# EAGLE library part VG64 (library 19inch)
PCB EUROCARD, 64-pin type C/AC, 2.54 mm

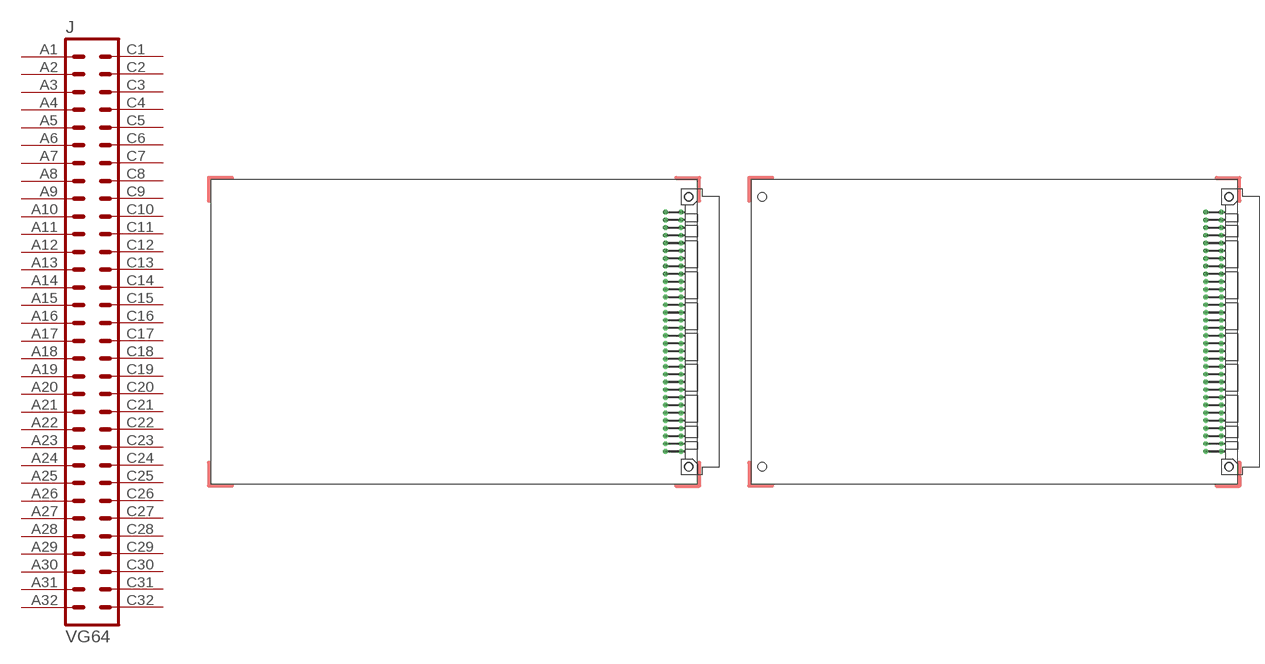
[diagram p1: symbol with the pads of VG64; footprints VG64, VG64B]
Designator prefix J

## VG64  [VG64]
A1  A1  pas
A2  A2  pas
A3  A3  pas
A4  A4  pas
A5  A5  pas
A6  A6  pas
A7  A7  pas
A8  A8  pas
A9  A9  pas
A10  A10  pas
A11  A11  pas
A12  A12  pas
A13  A13  pas
A14  A14  pas
A15  A15  pas
A16  A16  pas
A17  A17  pas
A18  A18  pas
A19  A19  pas
A20  A20  pas
A21  A21  pas
A22  A22  pas
A23  A23  pas
A24  A24  pas
A25  A25  pas
A26  A26  pas
A27  A27  pas
A28  A28  pas
A29  A29  pas
A30  A30  pas
A31  A31  pas
A32  A32  pas
C1  C1  pas
C2  C2  pas
C3  C3  pas
C4  C4  pas
C5  C5  pas
C6  C6  pas
C7  C7  pas
C8  C8  pas
C9  C9  pas
C10  C10  pas
C11  C11  pas
C12  C12  pas
C13  C13  pas
C14  C14  pas
C15  C15  pas
C16  C16  pas
C17  C17  pas
C18  C18  pas
C19  C19  pas
C20  C20  pas
C21  C21  pas
C22  C22  pas
C23  C23  pas
C24  C24  pas
C25  C25  pas
C26  C26  pas
C27  C27  pas
C28  C28  pas
C29  C29  pas
C30  C30  pas
C31  C31  pas
C32  C32  pas

## VG64B  [VG64B]
Pads as for VG64

## VG64K  [VG64K]
Pads as for VG64

## VG64KB  [VG64KB]
Pads as for VG64

## VG64P  [VG64P]
Pads as for VG64

## Footprint VG64 (pad centres in mm)
EUROCARD, 2 holes, C/AC, 2.54
drill 0.914 pad 1.6 round: A1 154.94,39.37
drill 0.914 pad 1.6 octagon: A2 154.94,36.83; A3 154.94,34.29; A4 154.94,31.75; A5 154.94,29.21; A6 154.94,26.67; A7 154.94,24.13; A8 154.94,21.59; A9 154.94,19.05; A10 154.94,16.51; A11 154.94,13.97; A12 154.94,11.43; A13 154.94,8.89; A14 154.94,6.35; A15 154.94,3.81; A16 154.94,1.27; A17 154.94,-1.27; A18 154.94,-3.81; A19 154.94,-6.35; A20 154.94,-8.89; A21 154.94,-11.43; A22 154.94,-13.97; A23 154.94,-16.51; A24 154.94,-19.05; A25 154.94,-21.59; A26 154.94,-24.13; A27 154.94,-26.67; A28 154.94,-29.21; A29 154.94,-31.75; A30 154.94,-34.29; A31 154.94,-36.83; A32 154.94,-39.37; C1 149.86,39.37; C2 149.86,36.83; C3 149.86,34.29; C4 149.86,31.75; C5 149.86,29.21; C6 149.86,26.67; C7 149.86,24.13; C8 149.86,21.59; C9 149.86,19.05; C10 149.86,16.51; C11 149.86,13.97; C12 149.86,11.43; C13 149.86,8.89; C14 149.86,6.35; C15 149.86,3.81; C16 149.86,1.27; C17 149.86,-1.27; C18 149.86,-3.81; C19 149.86,-6.35; C20 149.86,-8.89; C21 149.86,-11.43; C22 149.86,-13.97; C23 149.86,-16.51; C24 149.86,-19.05; C25 149.86,-21.59; C26 149.86,-24.13; C27 149.86,-26.67; C28 149.86,-29.21; C29 149.86,-31.75; C30 149.86,-34.29; C31 149.86,-36.83; C32 149.86,-39.37
hole 2.794 at 157.48,44.45
hole 2.794 at 157.48,-44.45

## Footprint VG64B (pad centres in mm)
EUROCARD, 4 holes, C/AC, 2.54
drill 0.914 pad 1.6 round: A1 154.94,39.37
drill 0.914 pad 1.6 octagon: A2 154.94,36.83; A3 154.94,34.29; A4 154.94,31.75; A5 154.94,29.21; A6 154.94,26.67; A7 154.94,24.13; A8 154.94,21.59; A9 154.94,19.05; A10 154.94,16.51; A11 154.94,13.97; A12 154.94,11.43; A13 154.94,8.89; A14 154.94,6.35; A15 154.94,3.81; A16 154.94,1.27; A17 154.94,-1.27; A18 154.94,-3.81; A19 154.94,-6.35; A20 154.94,-8.89; A21 154.94,-11.43; A22 154.94,-13.97; A23 154.94,-16.51; A24 154.94,-19.05; A25 154.94,-21.59; A26 154.94,-24.13; A27 154.94,-26.67; A28 154.94,-29.21; A29 154.94,-31.75; A30 154.94,-34.29; A31 154.94,-36.83; A32 154.94,-39.37; C1 149.86,39.37; C2 149.86,36.83; C3 149.86,34.29; C4 149.86,31.75; C5 149.86,29.21; C6 149.86,26.67; C7 149.86,24.13; C8 149.86,21.59; C9 149.86,19.05; C10 149.86,16.51; C11 149.86,13.97; C12 149.86,11.43; C13 149.86,8.89; C14 149.86,6.35; C15 149.86,3.81; C16 149.86,1.27; C17 149.86,-1.27; C18 149.86,-3.81; C19 149.86,-6.35; C20 149.86,-8.89; C21 149.86,-11.43; C22 149.86,-13.97; C23 149.86,-16.51; C24 149.86,-19.05; C25 149.86,-21.59; C26 149.86,-24.13; C27 149.86,-26.67; C28 149.86,-29.21; C29 149.86,-31.75; C30 149.86,-34.29; C31 149.86,-36.83; C32 149.86,-39.37
hole 2.794 at 157.48,44.45
hole 2.794 at 157.48,-44.45
hole 2.794 at 3.81,-44.45
hole 2.794 at 3.81,44.45

## Footprint VG64K (pad centres in mm)
EUROCARD, 2 holes, C/ABC, 2.54
drill 0.914 pad 1.6 round: A1 154.94,39.37
drill 0.914 pad 1.6 octagon: A2 154.94,36.83; A3 154.94,34.29; A4 154.94,31.75; A5 154.94,29.21; A6 154.94,26.67; A7 154.94,24.13; A8 154.94,21.59; A9 154.94,19.05; A10 154.94,16.51; A11 154.94,13.97; A12 154.94,11.43; A13 154.94,8.89; A14 154.94,6.35; A15 154.94,3.81; A16 154.94,1.27; A17 154.94,-1.27; A18 154.94,-3.81; A19 154.94,-6.35; A20 154.94,-8.89; A21 154.94,-11.43; A22 154.94,-13.97; A23 154.94,-16.51; A24 154.94,-19.05; A25 154.94,-21.59; A26 154.94,-24.13; A27 154.94,-26.67; A28 154.94,-29.21; A29 154.94,-31.75; A30 154.94,-34.29; A31 154.94,-36.83; A32 154.94,-39.37; C1 149.86,39.37; C2 149.86,36.83; C3 149.86,34.29; C4 149.86,31.75; C5 149.86,29.21; C6 149.86,26.67; C7 149.86,24.13; C8 149.86,21.59; C9 149.86,19.05; C10 149.86,16.51; C11 149.86,13.97; C12 149.86,11.43; C13 149.86,8.89; C14 149.86,6.35; C15 149.86,3.81; C16 149.86,1.27; C17 149.86,-1.27; C18 149.86,-3.81; C19 149.86,-6.35; C20 149.86,-8.89; C21 149.86,-11.43; C22 149.86,-13.97; C23 149.86,-16.51; C24 149.86,-19.05; C25 149.86,-21.59; C26 149.86,-24.13; C27 149.86,-26.67; C28 149.86,-29.21; C29 149.86,-31.75; C30 149.86,-34.29; C31 149.86,-36.83; C32 149.86,-39.37
hole 2.794 at 157.48,44.45
hole 2.794 at 157.48,-44.45

## Footprint VG64KB (pad centres in mm)
EUROCARD, 4 holes, C/AC, 2.54
drill 0.914 pad 1.6 round: A1 154.94,39.37
drill 0.914 pad 1.6 octagon: A2 154.94,36.83; A3 154.94,34.29; A4 154.94,31.75; A5 154.94,29.21; A6 154.94,26.67; A7 154.94,24.13; A8 154.94,21.59; A9 154.94,19.05; A10 154.94,16.51; A11 154.94,13.97; A12 154.94,11.43; A13 154.94,8.89; A14 154.94,6.35; A15 154.94,3.81; A16 154.94,1.27; A17 154.94,-1.27; A18 154.94,-3.81; A19 154.94,-6.35; A20 154.94,-8.89; A21 154.94,-11.43; A22 154.94,-13.97; A23 154.94,-16.51; A24 154.94,-19.05; A25 154.94,-21.59; A26 154.94,-24.13; A27 154.94,-26.67; A28 154.94,-29.21; A29 154.94,-31.75; A30 154.94,-34.29; A31 154.94,-36.83; A32 154.94,-39.37; C1 149.86,39.37; C2 149.86,36.83; C3 149.86,34.29; C4 149.86,31.75; C5 149.86,29.21; C6 149.86,26.67; C7 149.86,24.13; C8 149.86,21.59; C9 149.86,19.05; C10 149.86,16.51; C11 149.86,13.97; C12 149.86,11.43; C13 149.86,8.89; C14 149.86,6.35; C15 149.86,3.81; C16 149.86,1.27; C17 149.86,-1.27; C18 149.86,-3.81; C19 149.86,-6.35; C20 149.86,-8.89; C21 149.86,-11.43; C22 149.86,-13.97; C23 149.86,-16.51; C24 149.86,-19.05; C25 149.86,-21.59; C26 149.86,-24.13; C27 149.86,-26.67; C28 149.86,-29.21; C29 149.86,-31.75; C30 149.86,-34.29; C31 149.86,-36.83; C32 149.86,-39.37
hole 2.794 at 157.48,44.45
hole 2.794 at 157.48,-44.45
hole 2.794 at 3.81,-44.45
hole 2.794 at 3.81,44.45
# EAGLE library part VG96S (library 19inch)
PCB EUROCARD, 96-pin type C/ABC, 2.54 mm

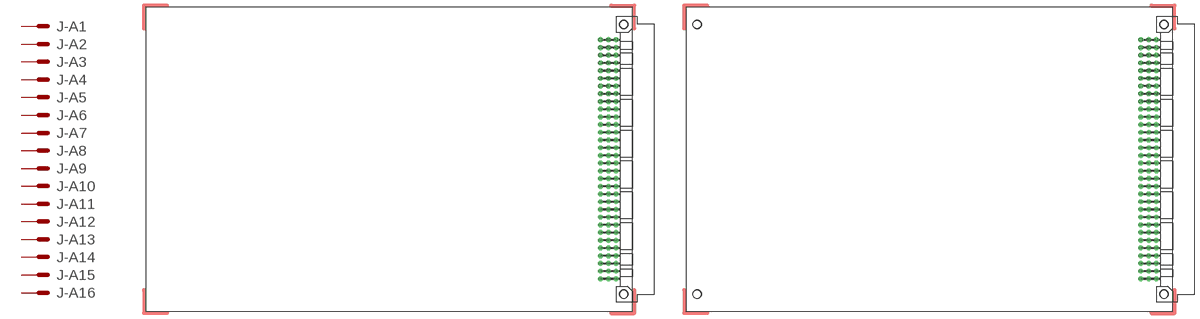
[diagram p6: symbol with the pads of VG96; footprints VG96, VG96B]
Designator prefix J; gates -A1=MS -A2=MS -A3=MS -A4=MS -A5=MS -A6=MS -A7=MS -A8=MS -A9=MS -A10=MS -A11=MS -A12=MS -A13=MS -A14=MS -A15=MS -A16=MS -A17=MS -A18=MS -A19=MS -A20=MS -A21=MS -A22=MS -A23=MS -A24=MS -A25=MS -A26=MS -A27=MS -A28=MS -A29=MS -A30=MS -A31=MS -A32=MS -B1=MS -B2=MS -B3=MS -B4=MS -B5=MS -B6=MS -B7=MS -B8=MS -B9=MS -B10=MS -B11=MS -B12=MS -B13=MS -B14=MS -B15=MS -B16=MS -B17=MS -B18=MS -B19=MS -B20=MS -B21=MS -B22=MS -B23=MS -B24=MS -B25=MS -B26=MS -B27=MS -B28=MS -B29=MS -B30=MS -B31=MS -B32=MS -C1=MS -C2=MS -C3=MS -C4=MS -C5=MS -C6=MS -C7=MS -C8=MS -C9=MS -C10=MS -C11=MS -C12=MS -C13=MS -C14=MS -C15=MS -C16=MS -C17=MS -C18=MS -C19=MS -C20=MS -C21=MS -C22=MS -C23=MS -C24=MS -C25=MS -C26=MS -C27=MS -C28=MS -C29=MS -C30=MS -C31=MS -C32=MSV

## VG96S  [VG96]
A1  -A1:MS  pas
A2  -A2:MS  pas
A3  -A3:MS  pas
A4  -A4:MS  pas
A5  -A5:MS  pas
A6  -A6:MS  pas
A7  -A7:MS  pas
A8  -A8:MS  pas
A9  -A9:MS  pas
A10  -A10:MS  pas
A11  -A11:MS  pas
A12  -A12:MS  pas
A13  -A13:MS  pas
A14  -A14:MS  pas
A15  -A15:MS  pas
A16  -A16:MS  pas
A17  -A17:MS  pas
A18  -A18:MS  pas
A19  -A19:MS  pas
A20  -A20:MS  pas
A21  -A21:MS  pas
A22  -A22:MS  pas
A23  -A23:MS  pas
A24  -A24:MS  pas
A25  -A25:MS  pas
A26  -A26:MS  pas
A27  -A27:MS  pas
A28  -A28:MS  pas
A29  -A29:MS  pas
A30  -A30:MS  pas
A31  -A31:MS  pas
A32  -A32:MS  pas
B1  -B1:MS  pas
B2  -B2:MS  pas
B3  -B3:MS  pas
B4  -B4:MS  pas
B5  -B5:MS  pas
B6  -B6:MS  pas
B7  -B7:MS  pas
B8  -B8:MS  pas
B9  -B9:MS  pas
B10  -B10:MS  pas
B11  -B11:MS  pas
B12  -B12:MS  pas
B13  -B13:MS  pas
B14  -B14:MS  pas
B15  -B15:MS  pas
B16  -B16:MS  pas
B17  -B17:MS  pas
B18  -B18:MS  pas
B19  -B19:MS  pas
B20  -B20:MS  pas
B21  -B21:MS  pas
B22  -B22:MS  pas
B23  -B23:MS  pas
B24  -B24:MS  pas
B25  -B25:MS  pas
B26  -B26:MS  pas
B27  -B27:MS  pas
B28  -B28:MS  pas
B29  -B29:MS  pas
B30  -B30:MS  pas
B31  -B31:MS  pas
B32  -B32:MS  pas
C1  -C1:MS  pas
C2  -C2:MS  pas
C3  -C3:MS  pas
C4  -C4:MS  pas
C5  -C5:MS  pas
C6  -C6:MS  pas
C7  -C7:MS  pas
C8  -C8:MS  pas
C9  -C9:MS  pas
C10  -C10:MS  pas
C11  -C11:MS  pas
C12  -C12:MS  pas
C13  -C13:MS  pas
C14  -C14:MS  pas
C15  -C15:MS  pas
C16  -C16:MS  pas
C17  -C17:MS  pas
C18  -C18:MS  pas
C19  -C19:MS  pas
C20  -C20:MS  pas
C21  -C21:MS  pas
C22  -C22:MS  pas
C23  -C23:MS  pas
C24  -C24:MS  pas
C25  -C25:MS  pas
C26  -C26:MS  pas
C27  -C27:MS  pas
C28  -C28:MS  pas
C29  -C29:MS  pas
C30  -C30:MS  pas
C31  -C31:MS  pas
C32  -C32:MSV  pas

## VG96SB  [VG96B]
Pads as for VG96

## VG96SK  [VG96K]
Pads as for VG96

## VG96SKB  [VG96KB]
Pads as for VG96

## VG96SP  [VG96P]
Pads as for VG96

## Footprint VG96 (pad centres in mm)
EUROCARD, C/ABC, 2.54
drill 0.914 pad 1.6 round: A1 154.94,39.37
drill 0.914 pad 1.6 octagon: A2 154.94,36.83; A3 154.94,34.29; A4 154.94,31.75; A5 154.94,29.21; A6 154.94,26.67; A7 154.94,24.13; A8 154.94,21.59; A9 154.94,19.05; A10 154.94,16.51; A11 154.94,13.97; A12 154.94,11.43; A13 154.94,8.89; A14 154.94,6.35; A15 154.94,3.81; A16 154.94,1.27; A17 154.94,-1.27; A18 154.94,-3.81; A19 154.94,-6.35; A20 154.94,-8.89; A21 154.94,-11.43; A22 154.94,-13.97; A23 154.94,-16.51; A24 154.94,-19.05; A25 154.94,-21.59; A26 154.94,-24.13; A27 154.94,-26.67; A28 154.94,-29.21; A29 154.94,-31.75; A30 154.94,-34.29; A31 154.94,-36.83; A32 154.94,-39.37; B1 152.4,39.37; B2 152.4,36.83; B3 152.4,34.29; B4 152.4,31.75; B5 152.4,29.21; B6 152.4,26.67; B7 152.4,24.13; B8 152.4,21.59; B9 152.4,19.05; B10 152.4,16.51; B11 152.4,13.97; B12 152.4,11.43; B13 152.4,8.89; B14 152.4,6.35; B15 152.4,3.81; B16 152.4,1.27; B17 152.4,-1.27; B18 152.4,-3.81; B19 152.4,-6.35; B20 152.4,-8.89; B21 152.4,-11.43; B22 152.4,-13.97; B23 152.4,-16.51; B24 152.4,-19.05; B25 152.4,-21.59; B26 152.4,-24.13; B27 152.4,-26.67; B28 152.4,-29.21; B29 152.4,-31.75; B30 152.4,-34.29; B31 152.4,-36.83; B32 152.4,-39.37; C1 149.86,39.37; C2 149.86,36.83; C3 149.86,34.29; C4 149.86,31.75; C5 149.86,29.21; C6 149.86,26.67; C7 149.86,24.13; C8 149.86,21.59; C9 149.86,19.05; C10 149.86,16.51; C11 149.86,13.97; C12 149.86,11.43; C13 149.86,8.89; C14 149.86,6.35; C15 149.86,3.81; C16 149.86,1.27; C17 149.86,-1.27; C18 149.86,-3.81; C19 149.86,-6.35; C20 149.86,-8.89; C21 149.86,-11.43; C22 149.86,-13.97; C23 149.86,-16.51; C24 149.86,-19.05; C25 149.86,-21.59; C26 149.86,-24.13; C27 149.86,-26.67; C28 149.86,-29.21; C29 149.86,-31.75; C30 149.86,-34.29; C31 149.86,-36.83; C32 149.86,-39.37
hole 2.794 at 157.48,44.45
hole 2.794 at 157.48,-44.45

## Footprint VG96B (pad centres in mm)
EUROCARD, 4 holes, C/ABC, 2.54
drill 0.914 pad 1.6 round: A1 154.94,39.37
drill 0.914 pad 1.6 octagon: A2 154.94,36.83; A3 154.94,34.29; A4 154.94,31.75; A5 154.94,29.21; A6 154.94,26.67; A7 154.94,24.13; A8 154.94,21.59; A9 154.94,19.05; A10 154.94,16.51; A11 154.94,13.97; A12 154.94,11.43; A13 154.94,8.89; A14 154.94,6.35; A15 154.94,3.81; A16 154.94,1.27; A17 154.94,-1.27; A18 154.94,-3.81; A19 154.94,-6.35; A20 154.94,-8.89; A21 154.94,-11.43; A22 154.94,-13.97; A23 154.94,-16.51; A24 154.94,-19.05; A25 154.94,-21.59; A26 154.94,-24.13; A27 154.94,-26.67; A28 154.94,-29.21; A29 154.94,-31.75; A30 154.94,-34.29; A31 154.94,-36.83; A32 154.94,-39.37; B1 152.4,39.37; B2 152.4,36.83; B3 152.4,34.29; B4 152.4,31.75; B5 152.4,29.21; B6 152.4,26.67; B7 152.4,24.13; B8 152.4,21.59; B9 152.4,19.05; B10 152.4,16.51; B11 152.4,13.97; B12 152.4,11.43; B13 152.4,8.89; B14 152.4,6.35; B15 152.4,3.81; B16 152.4,1.27; B17 152.4,-1.27; B18 152.4,-3.81; B19 152.4,-6.35; B20 152.4,-8.89; B21 152.4,-11.43; B22 152.4,-13.97; B23 152.4,-16.51; B24 152.4,-19.05; B25 152.4,-21.59; B26 152.4,-24.13; B27 152.4,-26.67; B28 152.4,-29.21; B29 152.4,-31.75; B30 152.4,-34.29; B31 152.4,-36.83; B32 152.4,-39.37; C1 149.86,39.37; C2 149.86,36.83; C3 149.86,34.29; C4 149.86,31.75; C5 149.86,29.21; C6 149.86,26.67; C7 149.86,24.13; C8 149.86,21.59; C9 149.86,19.05; C10 149.86,16.51; C11 149.86,13.97; C12 149.86,11.43; C13 149.86,8.89; C14 149.86,6.35; C15 149.86,3.81; C16 149.86,1.27; C17 149.86,-1.27; C18 149.86,-3.81; C19 149.86,-6.35; C20 149.86,-8.89; C21 149.86,-11.43; C22 149.86,-13.97; C23 149.86,-16.51; C24 149.86,-19.05; C25 149.86,-21.59; C26 149.86,-24.13; C27 149.86,-26.67; C28 149.86,-29.21; C29 149.86,-31.75; C30 149.86,-34.29; C31 149.86,-36.83; C32 149.86,-39.37
hole 2.794 at 157.48,44.45
hole 2.794 at 157.48,-44.45
hole 2.794 at 3.81,44.45
hole 2.794 at 3.81,-44.45

## Footprint VG96K (pad centres in mm)
EUROCARD, 2 holes, C/ABC, 2.54
drill 0.914 pad 1.6 round: A1 154.94,39.37
drill 0.914 pad 1.6 octagon: A2 154.94,36.83; A3 154.94,34.29; A4 154.94,31.75; A5 154.94,29.21; A6 154.94,26.67; A7 154.94,24.13; A8 154.94,21.59; A9 154.94,19.05; A10 154.94,16.51; A11 154.94,13.97; A12 154.94,11.43; A13 154.94,8.89; A14 154.94,6.35; A15 154.94,3.81; A16 154.94,1.27; A17 154.94,-1.27; A18 154.94,-3.81; A19 154.94,-6.35; A20 154.94,-8.89; A21 154.94,-11.43; A22 154.94,-13.97; A23 154.94,-16.51; A24 154.94,-19.05; A25 154.94,-21.59; A26 154.94,-24.13; A27 154.94,-26.67; A28 154.94,-29.21; A29 154.94,-31.75; A30 154.94,-34.29; A31 154.94,-36.83; A32 154.94,-39.37; B1 152.4,39.37; B2 152.4,36.83; B3 152.4,34.29; B4 152.4,31.75; B5 152.4,29.21; B6 152.4,26.67; B7 152.4,24.13; B8 152.4,21.59; B9 152.4,19.05; B10 152.4,16.51; B11 152.4,13.97; B12 152.4,11.43; B13 152.4,8.89; B14 152.4,6.35; B15 152.4,3.81; B16 152.4,1.27; B17 152.4,-1.27; B18 152.4,-3.81; B19 152.4,-6.35; B20 152.4,-8.89; B21 152.4,-11.43; B22 152.4,-13.97; B23 152.4,-16.51; B24 152.4,-19.05; B25 152.4,-21.59; B26 152.4,-24.13; B27 152.4,-26.67; B28 152.4,-29.21; B29 152.4,-31.75; B30 152.4,-34.29; B31 152.4,-36.83; B32 152.4,-39.37; C1 149.86,39.37; C2 149.86,36.83; C3 149.86,34.29; C4 149.86,31.75; C5 149.86,29.21; C6 149.86,26.67; C7 149.86,24.13; C8 149.86,21.59; C9 149.86,19.05; C10 149.86,16.51; C11 149.86,13.97; C12 149.86,11.43; C13 149.86,8.89; C14 149.86,6.35; C15 149.86,3.81; C16 149.86,1.27; C17 149.86,-1.27; C18 149.86,-3.81; C19 149.86,-6.35; C20 149.86,-8.89; C21 149.86,-11.43; C22 149.86,-13.97; C23 149.86,-16.51; C24 149.86,-19.05; C25 149.86,-21.59; C26 149.86,-24.13; C27 149.86,-26.67; C28 149.86,-29.21; C29 149.86,-31.75; C30 149.86,-34.29; C31 149.86,-36.83; C32 149.86,-39.37
hole 2.794 at 157.48,44.45
hole 2.794 at 157.48,-44.45

## Footprint VG96KB (pad centres in mm)
EUROCARD, 4 holes, C/ABC, 2.54
drill 0.914 pad 1.6 round: A1 154.94,39.37
drill 0.914 pad 1.6 octagon: A2 154.94,36.83; A3 154.94,34.29; A4 154.94,31.75; A5 154.94,29.21; A6 154.94,26.67; A7 154.94,24.13; A8 154.94,21.59; A9 154.94,19.05; A10 154.94,16.51; A11 154.94,13.97; A12 154.94,11.43; A13 154.94,8.89; A14 154.94,6.35; A15 154.94,3.81; A16 154.94,1.27; A17 154.94,-1.27; A18 154.94,-3.81; A19 154.94,-6.35; A20 154.94,-8.89; A21 154.94,-11.43; A22 154.94,-13.97; A23 154.94,-16.51; A24 154.94,-19.05; A25 154.94,-21.59; A26 154.94,-24.13; A27 154.94,-26.67; A28 154.94,-29.21; A29 154.94,-31.75; A30 154.94,-34.29; A31 154.94,-36.83; A32 154.94,-39.37; B1 152.4,39.37; B2 152.4,36.83; B3 152.4,34.29; B4 152.4,31.75; B5 152.4,29.21; B6 152.4,26.67; B7 152.4,24.13; B8 152.4,21.59; B9 152.4,19.05; B10 152.4,16.51; B11 152.4,13.97; B12 152.4,11.43; B13 152.4,8.89; B14 152.4,6.35; B15 152.4,3.81; B16 152.4,1.27; B17 152.4,-1.27; B18 152.4,-3.81; B19 152.4,-6.35; B20 152.4,-8.89; B21 152.4,-11.43; B22 152.4,-13.97; B23 152.4,-16.51; B24 152.4,-19.05; B25 152.4,-21.59; B26 152.4,-24.13; B27 152.4,-26.67; B28 152.4,-29.21; B29 152.4,-31.75; B30 152.4,-34.29; B31 152.4,-36.83; B32 152.4,-39.37; C1 149.86,39.37; C2 149.86,36.83; C3 149.86,34.29; C4 149.86,31.75; C5 149.86,29.21; C6 149.86,26.67; C7 149.86,24.13; C8 149.86,21.59; C9 149.86,19.05; C10 149.86,16.51; C11 149.86,13.97; C12 149.86,11.43; C13 149.86,8.89; C14 149.86,6.35; C15 149.86,3.81; C16 149.86,1.27; C17 149.86,-1.27; C18 149.86,-3.81; C19 149.86,-6.35; C20 149.86,-8.89; C21 149.86,-11.43; C22 149.86,-13.97; C23 149.86,-16.51; C24 149.86,-19.05; C25 149.86,-21.59; C26 149.86,-24.13; C27 149.86,-26.67; C28 149.86,-29.21; C29 149.86,-31.75; C30 149.86,-34.29; C31 149.86,-36.83; C32 149.86,-39.37
hole 2.794 at 157.48,44.45
hole 2.794 at 157.48,-44.45
hole 2.794 at 3.81,44.45
hole 2.794 at 3.81,-44.45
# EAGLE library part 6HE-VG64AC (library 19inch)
Euro Card with 2 x VG-64 AC connector

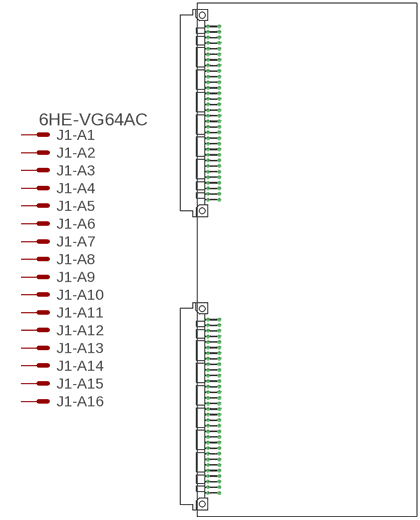
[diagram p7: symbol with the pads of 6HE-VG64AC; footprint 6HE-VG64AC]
Designator prefix J; gates 1-A1=MSV 1-A2=MS 1-A3=MS 1-A4=MS 1-A5=MS 1-A6=MS 1-A7=MS 1-A8=MS 1-A9=MS 1-A10=MS 1-A11=MS 1-A12=MS 1-A13=MS 1-A14=MS 1-A15=MS 1-A16=MS 1-A17=MS 1-A18=MS 1-A19=MS 1-A20=MS 1-A21=MS 1-A22=MS 1-A23=MS 1-A24=MS 1-A25=MS 1-A26=MS 1-A27=MS 1-A28=MS 1-A29=MS 1-A30=MS 1-A31=MS 1-A32=MS 1-C1=MSV 1-C2=MS 1-C3=MS 1-C4=MS 1-C5=MS 1-C6=MS 1-C7=MS 1-C8=MS 1-C9=MS 1-C10=MS 1-C11=MS 1-C12=MS 1-C13=MS 1-C14=MS 1-C15=MS 1-C16=MS 1-C17=MS 1-C18=MS 1-C19=MS 1-C20=MS 1-C21=MS 1-C22=MS 1-C23=MS 1-C24=MS 1-C25=MS 1-C26=MS 1-C27=MS 1-C28=MS 1-C29=MS 1-C30=MS 1-C31=MS 1-C32=MS 2-A1=MSV 2-A2=MS 2-A3=MS 2-A4=MS 2-A5=MS 2-A6=MS 2-A7=MS 2-A8=MS 2-A9=MS 2-A10=MS 2-A11=MS 2-A12=MS 2-A13=MS 2-A14=MS 2-A15=MS 2-A16=MS 2-A17=MS 2-A18=MS 2-A19=MS 2-A20=MS 2-A21=MS 2-A22=MS 2-A23=MS 2-A24=MS 2-A25=MS 2-A26=MS 2-A27=MS 2-A28=MS 2-A29=MS 2-A30=MS 2-A31=MS 2-A32=MS 2-C1=MSV 2-C2=MS 2-C3=MS 2-C4=MS 2-C5=MS 2-C6=MS 2-C7=MS 2-C8=MS 2-C9=MS 2-C10=MS 2-C11=MS 2-C12=MS 2-C13=MS 2-C14=MS 2-C15=MS 2-C16=MS 2-C17=MS 2-C18=MS 2-C19=MS 2-C20=MS 2-C21=MS 2-C22=MS 2-C23=MS 2-C24=MS 2-C25=MS 2-C26=MS 2-C27=MS 2-C28=MS 2-C29=MS 2-C30=MS 2-C31=MS 2-C32=MS

## 6HE-VG64AC  [6HE-VG64AC]
1-A1  1-A1:MSV  pas
1-A2  1-A2:MS  pas
1-A3  1-A3:MS  pas
1-A4  1-A4:MS  pas
1-A5  1-A5:MS  pas
1-A6  1-A6:MS  pas
1-A7  1-A7:MS  pas
1-A8  1-A8:MS  pas
1-A9  1-A9:MS  pas
1-A10  1-A10:MS  pas
1-A11  1-A11:MS  pas
1-A12  1-A12:MS  pas
1-A13  1-A13:MS  pas
1-A14  1-A14:MS  pas
1-A15  1-A15:MS  pas
1-A16  1-A16:MS  pas
1-A17  1-A17:MS  pas
1-A18  1-A18:MS  pas
1-A19  1-A19:MS  pas
1-A20  1-A20:MS  pas
1-A21  1-A21:MS  pas
1-A22  1-A22:MS  pas
1-A23  1-A23:MS  pas
1-A24  1-A24:MS  pas
1-A25  1-A25:MS  pas
1-A26  1-A26:MS  pas
1-A27  1-A27:MS  pas
1-A28  1-A28:MS  pas
1-A29  1-A29:MS  pas
1-A30  1-A30:MS  pas
1-A31  1-A31:MS  pas
1-A32  1-A32:MS  pas
1-C1  1-C1:MSV  pas
1-C2  1-C2:MS  pas
1-C3  1-C3:MS  pas
1-C4  1-C4:MS  pas
1-C5  1-C5:MS  pas
1-C6  1-C6:MS  pas
1-C7  1-C7:MS  pas
1-C8  1-C8:MS  pas
1-C9  1-C9:MS  pas
1-C10  1-C10:MS  pas
1-C11  1-C11:MS  pas
1-C12  1-C12:MS  pas
1-C13  1-C13:MS  pas
1-C14  1-C14:MS  pas
1-C15  1-C15:MS  pas
1-C16  1-C16:MS  pas
1-C17  1-C17:MS  pas
1-C18  1-C18:MS  pas
1-C19  1-C19:MS  pas
1-C20  1-C20:MS  pas
1-C21  1-C21:MS  pas
1-C22  1-C22:MS  pas
1-C23  1-C23:MS  pas
1-C24  1-C24:MS  pas
1-C25  1-C25:MS  pas
1-C26  1-C26:MS  pas
1-C27  1-C27:MS  pas
1-C28  1-C28:MS  pas
1-C29  1-C29:MS  pas
1-C30  1-C30:MS  pas
1-C31  1-C31:MS  pas
1-C32  1-C32:MS  pas
2-A1  2-A1:MSV  pas
2-A2  2-A2:MS  pas
2-A3  2-A3:MS  pas
2-A4  2-A4:MS  pas
2-A5  2-A5:MS  pas
2-A6  2-A6:MS  pas
2-A7  2-A7:MS  pas
2-A8  2-A8:MS  pas
2-A9  2-A9:MS  pas
2-A10  2-A10:MS  pas
2-A11  2-A11:MS  pas
2-A12  2-A12:MS  pas
2-A13  2-A13:MS  pas
2-A14  2-A14:MS  pas
2-A15  2-A15:MS  pas
2-A16  2-A16:MS  pas
2-A17  2-A17:MS  pas
2-A18  2-A18:MS  pas
2-A19  2-A19:MS  pas
2-A20  2-A20:MS  pas
2-A21  2-A21:MS  pas
2-A22  2-A22:MS  pas
2-A23  2-A23:MS  pas
2-A24  2-A24:MS  pas
2-A25  2-A25:MS  pas
2-A26  2-A26:MS  pas
2-A27  2-A27:MS  pas
2-A28  2-A28:MS  pas
2-A29  2-A29:MS  pas
2-A30  2-A30:MS  pas
2-A31  2-A31:MS  pas
2-A32  2-A32:MS  pas
2-C1  2-C1:MSV  pas
2-C2  2-C2:MS  pas
2-C3  2-C3:MS  pas
2-C4  2-C4:MS  pas
2-C5  2-C5:MS  pas
2-C6  2-C6:MS  pas
2-C7  2-C7:MS  pas
2-C8  2-C8:MS  pas
2-C9  2-C9:MS  pas
2-C10  2-C10:MS  pas
2-C11  2-C11:MS  pas
2-C12  2-C12:MS  pas
2-C13  2-C13:MS  pas
2-C14  2-C14:MS  pas
2-C15  2-C15:MS  pas
2-C16  2-C16:MS  pas
2-C17  2-C17:MS  pas
2-C18  2-C18:MS  pas
2-C19  2-C19:MS  pas
2-C20  2-C20:MS  pas
2-C21  2-C21:MS  pas
2-C22  2-C22:MS  pas
2-C23  2-C23:MS  pas
2-C24  2-C24:MS  pas
2-C25  2-C25:MS  pas
2-C26  2-C26:MS  pas
2-C27  2-C27:MS  pas
2-C28  2-C28:MS  pas
2-C29  2-C29:MS  pas
2-C30  2-C30:MS  pas
2-C31  2-C31:MS  pas
2-C32  2-C32:MS  pas

## Footprint 6HE-VG64AC (pad centres in mm)
EUROCARD 6HE with 2 x VG64 AC connector
drill 0.914 pad 1.6 octagon: 1-A1 5.08,11.43; 1-A2 5.08,16.51; 1-A3 5.08,13.97; 1-A4 5.08,19.05; 1-A5 5.08,21.59; 1-A6 5.08,24.13; 1-A7 5.08,26.67; 1-A8 5.08,29.21; 1-A9 5.08,31.75; 1-A10 5.08,34.29; 1-A11 5.08,36.83; 1-A12 5.08,39.37; 1-A13 5.08,41.91; 1-A14 5.08,44.45; 1-A15 5.08,46.99; 1-A16 5.08,49.53; 1-A17 5.08,52.07; 1-A18 5.08,54.61; 1-A19 5.08,57.15; 1-A20 5.08,59.69; 1-A21 5.08,62.23; 1-A22 5.08,64.77; 1-A23 5.08,67.31; 1-A24 5.08,69.85; 1-A25 5.08,72.39; 1-A26 5.08,74.93; 1-A27 5.08,77.47; 1-A28 5.08,80.01; 1-A29 5.08,82.55; 1-A30 5.08,85.09; 1-A31 5.08,87.63; 1-A32 5.08,90.17; 1-C1 10.16,11.43; 1-C2 10.16,13.97; 1-C3 10.16,16.51; 1-C4 10.16,19.05; 1-C5 10.16,21.59; 1-C6 10.16,24.13; 1-C7 10.16,26.67; 1-C8 10.16,29.21; 1-C9 10.16,31.75; 1-C10 10.16,34.29; 1-C11 10.16,36.83; 1-C12 10.16,39.37; 1-C13 10.16,41.91; 1-C14 10.16,44.45; 1-C15 10.16,46.99; 1-C16 10.16,49.53; 1-C17 10.16,52.07; 1-C18 10.16,54.61; 1-C19 10.16,57.15; 1-C20 10.16,59.69; 1-C21 10.16,62.23; 1-C22 10.16,64.77; 1-C23 10.16,67.31; 1-C24 10.16,69.85; 1-C25 10.16,72.39; 1-C26 10.16,74.93; 1-C27 10.16,77.47; 1-C28 10.16,80.01; 1-C29 10.16,82.55; 1-C30 10.16,85.09; 1-C31 10.16,87.63; 1-C32 10.16,90.17; 2-A1 5.08,144.78; 2-A2 5.08,147.32; 2-A3 5.08,149.86; 2-A4 5.08,152.4; 2-A5 5.08,154.94; 2-A6 5.08,157.48; 2-A7 5.08,160.02; 2-A8 5.08,162.56; 2-A9 5.08,165.1; 2-A10 5.08,167.64; 2-A11 5.08,170.18; 2-A12 5.08,172.72; 2-A13 5.08,175.26; 2-A14 5.08,177.8; 2-A15 5.08,180.34; 2-A16 5.08,182.88; 2-A17 5.08,185.42; 2-A18 5.08,187.96; 2-A19 5.08,190.5; 2-A20 5.08,193.04; 2-A21 5.08,195.58; 2-A22 5.08,198.12; 2-A23 5.08,200.66; 2-A24 5.08,203.2; 2-A25 5.08,205.74; 2-A26 5.08,208.28; 2-A27 5.08,210.82; 2-A28 5.08,213.36; 2-A29 5.08,215.9; 2-A30 5.08,218.44; 2-A31 5.08,220.98; 2-A32 5.08,223.52; 2-C1 10.16,144.78; 2-C2 10.16,147.32; 2-C3 10.16,149.86; 2-C4 10.16,152.4; 2-C5 10.16,154.94; 2-C6 10.16,157.48; 2-C7 10.16,160.02; 2-C8 10.16,162.56; 2-C9 10.16,165.1; 2-C10 10.16,167.64; 2-C11 10.16,170.18; 2-C12 10.16,172.72; 2-C13 10.16,175.26; 2-C14 10.16,177.8; 2-C15 10.16,180.34; 2-C16 10.16,182.88; 2-C17 10.16,185.42; 2-C18 10.16,187.96; 2-C19 10.16,190.5; 2-C20 10.16,193.04; 2-C21 10.16,195.58; 2-C22 10.16,198.12; 2-C23 10.16,200.66; 2-C24 10.16,203.2; 2-C25 10.16,205.74; 2-C26 10.16,208.28; 2-C27 10.16,210.82; 2-C28 10.16,213.36; 2-C29 10.16,215.9; 2-C30 10.16,218.44; 2-C31 10.16,220.98; 2-C32 10.16,223.52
